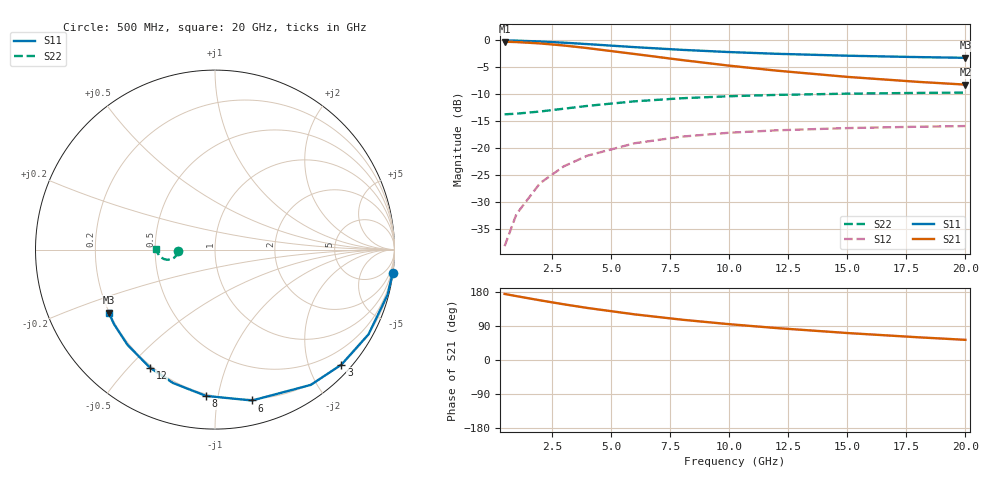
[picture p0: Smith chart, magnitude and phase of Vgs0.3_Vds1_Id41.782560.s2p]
# Hz S RI R 50
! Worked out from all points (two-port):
!   12 points, 500 MHz to 20 GHz, reference 50 ohm
!   highest |S21| = -0.25 dB at 500 MHz (marker M1); lowest = -8.2 dB at 20 GHz (marker M2)
!   |S21| within 3 dB of the highest: start of sweep to 7.281 GHz
!   lowest |S11| = -3.2 dB at 20 GHz (marker M3), VSWR 5.43, Z = 9.88 - j13.2 ohm
!   |S11| at or under -10 dB: nowhere
!   |S22| runs from -13.7 to -9.7 dB; largest |S21 - S12| = 0.97
!   S11 on the Smith chart (normalised r, x): 500 MHz: 0, -16; 3 GHz: 0.19, -2.57; 6 GHz: 0.19, -1.26; 8 GHz: 0.19, -0.92; 12 GHz: 0.19, -0.57; 20 GHz: 0.20, -0.26
5e8  0.9902 -0.128  -0.9672 0.0971  0.000994 0.0122  -0.2057 -0.00917
1e9  0.9615 -0.2517  -0.9457 0.1911  0.00391 0.0241  -0.2079 -0.018
2e9  0.8554 -0.472  -0.866 0.3587  0.0147 0.0449  -0.216 -0.0336
3e9  0.7043 -0.6409  -0.7526 0.4877  0.0301 0.0606  -0.2276 -0.0453
4e9  0.5336 -0.7539  -0.6243 0.5747  0.0474 0.0705  -0.2407 -0.0527
6e9  0.2071 -0.8406  -0.3789 0.6445  0.0806 0.0762  -0.2658 -0.0568
8e9  -0.0501 -0.8153  -0.1852 0.6303  0.1066 0.0705  -0.2856 -0.0522
1e10  -0.2343 -0.7431  -0.046 0.5809  0.1252 0.06  -0.2998 -0.0439
1.2e10  -0.363 -0.6573  0.0519 0.5214  0.138 0.0481  -0.3098 -0.0343
1.5e10  -0.4875 -0.5307  0.1478 0.4339  0.1503 0.0306  -0.3196 -0.0198
1.8e10  -0.5613 -0.4177  0.2064 0.3566  0.1573 0.0144  -0.3253 -0.00579
2e10  -0.593 -0.3505  0.2327 0.3111  0.1601 0.00436  -0.3275 0.00322
